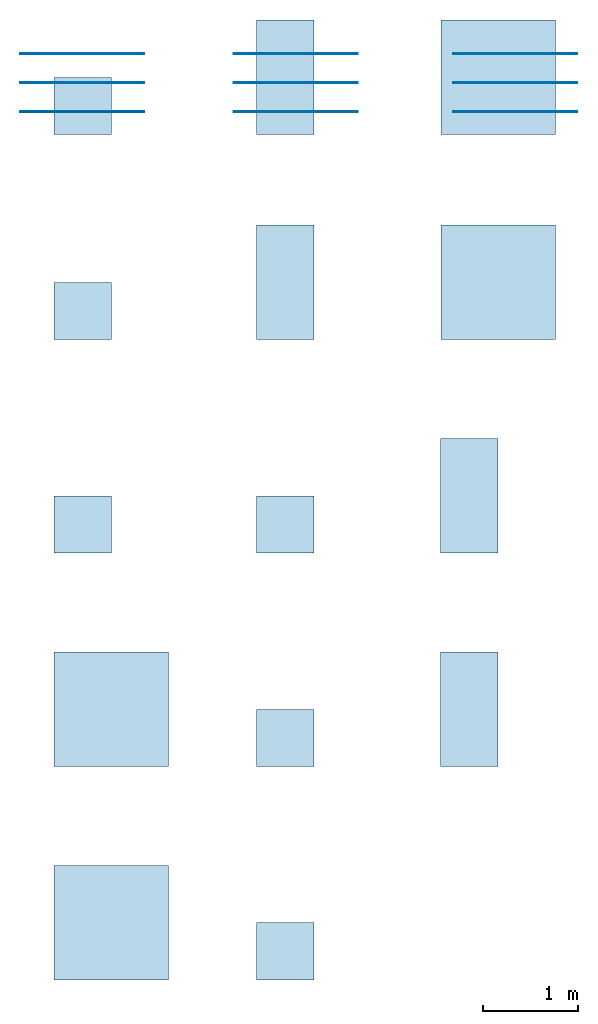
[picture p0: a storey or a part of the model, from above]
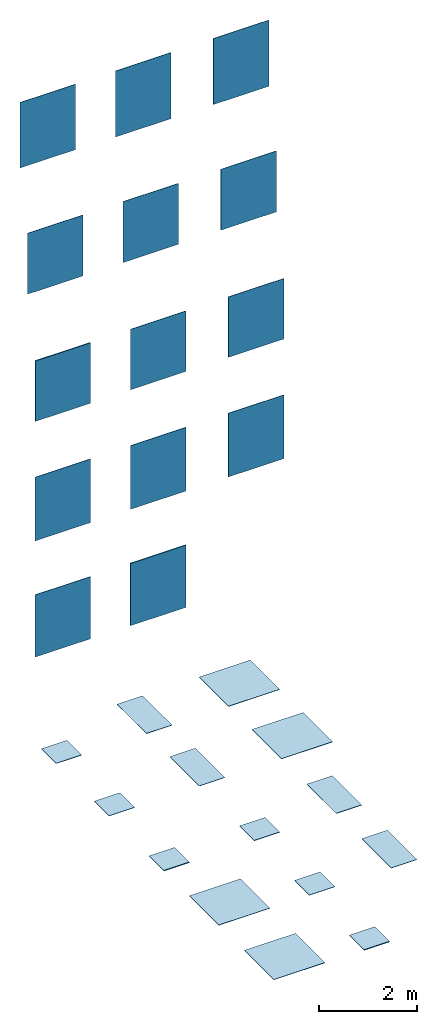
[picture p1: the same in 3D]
Properties of the parts of a building model (IFC2X3), part 2 of 4

# IfcSlab: Floor:Floor_Tiles_Refin-Orobica-Bianca-60x120 OQ59, Floor:Floor_Tiles_Refin-Orobica-Bianca-60x120 OQ59:339650
Type - COBie - AccessibilityPerformance: N/A; AssetIdentifier: N/A; AssetType: FIXED; BarCode: N/A; Category: Pr_35_93_96_19:Ceramic tiles; CodePerformance: BS 5385; Color: WHITE; Constituents: N/A; Description: PORCELAIN STONEWARE TILE; DurationUnit: YEAR; ExpectedLife: N/A; Features: N/A; Grade: N/A; InstallationDate: 31/12/1900 23:59:59; Manufacturer: info@refin.it; Material: PORCELAIN STONEWARE; ModelNumber: OQ59; ModelReference: OQ59; Name: Orobica_Bianca_60X120 R; NominalHeight: 9 mm; NominalLength: 600 mm; NominalWidth: 1200 mm; ReplacementCost: N/A; SerialNumber: N/A; Shape: RECTANGULAR; Size: 60X120; SustainabilityPerformance: N/A; TagNumber: N/A; WarrantyDescription: N/A; WarrantyDurationLabor: N/A; WarrantyDurationParts: N/A; WarrantyDurationUnit: YEAR; WarrantyGuarantorLabor: N/A; WarrantyGuarantorParts: N/A; WarrantyStartDate: 31/12/1900 23:59:59
Type - DoPAndProductCertification - HarmonizedTechnicalSpecification: EN 14411:2015; DeclarationPerformanceNumber: CPR_01; UniqueIdentificationCodeOfTheProductType: Dry-pressed ceramic tiles,with water absorption Eb<0,5%; SystemOfAssessmentAndVerificationOfCostancyOfPperformance (AVCP): SYSTEM 4; NameAndIdentificationNumberOfNotifiedLaboratory: N/A; CertificateNumber: N/A; ReactionToFire: A1FL/A1; ReleaseOfDangerousSubstanceCadmium: NPD mg/dm2; ReleaseOfDangerousSubstanceLead: NPD mg/dm2; BreakingStrength: > 1300 N; BondStrengthAdhesion: NPD N/mm2; ThermalShockResistance: PASS; Tactility: NPD; DurabilityForInternalUse: PASS; DurabilityExternalUseFreezeThawResistance: PASS; VoluntaryOrNotSubjectToCEMarking: Y/N; IntendedUse: INTERNAL/EXTERNAL; TensileStrengthOrModulusOfRupture: > 35 N/mm2; SlipperinessDIN51130_RampWithOil: R10; SlipperinessDIN51097_RampBarefoot: N/A; SlipperinessDIN51131_Tribometer: N/A; SlipperinessENV12633_PendulumTester: RD = N/A; SlipperinessXPCENTS16165_RampTest: N/A; SlipperinessBCRA_Tribometer: Asciutto > 0,40 / Bagnato > 0,40; SlipperinessBOT3000_Tribometer: > 0,42 Wet; UPECMarkCertification: N/A; UNIMarkCertification: N/A
Type - OtherThecnicalFeatures - DimensionsLengthAndWidth: 0.3; DimensionsThickness: 5; DimensionsStraightness: 0.3; DimensionsRectangularity: 0.3; DimensionsSurfaceFlatness: 0.4; SurfaceQuality: 5; WaterAbsorption: Ev<0.5%; ApparentDensity: N/A g/cm3; ModulusOfRupture: > 35 N/mm2; ImpactResistance: > 0.55; DeepAbrasionResistance: < 175 mm3; SurfaceAbrasionResistance: N/A (classe); LinearThermalExpansion: < 7 10-6/°C; MoistureExpansion: < 0.01; CrazingResistance: N/A; FrostResistance: RESISTENTE; ChemicalResistance: A,LA,HA (classe); StainsResistance: 5 (classe); ThermalConductivity: 1.3 W/m.K; ElectricalConductivity: N/A MW; CompressionResistance: 250 Mpa; HardnessMohsScale: N/A (classe); Light ReflectanceValueLRV: 56 %; LightAndColourFastness: N/A; AntibacterialProperties: N/A (numero puro)
Type - Ambiental Sustainability - EPDType: PRODUCT-SPECIFIC TYPE III EPD; EPDDocument: https://www.refin.it/download/certifications/REFIN_EPD_it.pdf; EnvironmentalProductDeclarationEPD: Y; ISO9001Certification: https://www.refin.it/download/certifications/iso9001.pdf; Ecolabel UE: Y/N; EcolabelCertification: https://www.refin.it/download/certifications/PEF_CeramicheRefin_IT.pdf; EMASCertification/Document: N/A; HealthProductDeclarationHPDCertification/self declaration: N/A; FicheDeDéclarationEnvironnementaleEtSanitaireFDESCertification: https://www.refin.it/download/certifications/refin_fdes.pdf; RecycledContentPreconsumerCertification: https://www.refin.it/download/certifications/leed.pdf; SolarReflectance_InitialValue: 72; SolarReflectance_After3YearValue: N/A; SolarReflectanceCertification: N/A; SolarReflectanceIndexSRICertification: N/A; ZeroVOCMineralBasedProduct: Y; VOCIndoorAirQualityCertification: N/A; RawMaterialSourceAndExtractionDocument: N/A; RecyclableProductPackaging: Y; REACHCompliant: Y; AsbestosFreeMaterial: Y; FormaldehydeFreeMaterial: Y; CAMCompliantDeclaration: N/A; ISO45001Certification: N/A; ISO50001Certification: N/A
Type - Pset_EnvironmentalImpactIndicator - Reference: N/A; FunctionalUnitReference: N/A; Unit: m2; LifeCyclePhase: A1,A2,A3,A4,A5,B1,B2,B3,B4,B5,B6,B7,C1,C2,C3,C4,D; ExpectedServiceLife: 60 YEARS; TotalPrimaryEnergyConsumptionPerUnit: 234; WaterConsumptionPerUnit: 0.0522; HazardousWastePerUnit: 0.00301; NonHazardousWastePerUnit: 10.4; ClimateChangePerUnit: 12.8; AtmosphericAcidificationPerUnit: 0.0485; RenewableEnergyConsumptionPerUnit: 44.5; NonRenewableEnergyConsumptionPerUnit: 189; ResourceDepletionPerUnit: 0.0000365; InertWastePerUnit: N/A; RadioactiveWastePerUnit: 0.00254; StratosphericOzoneLayerDestructionPerUnit: 0.0000000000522; PhotochemicalOzoneFormationPerUnit: 0.00302; EutrophicationPerUnit: 0.00445
Type - Pset_EnvironmentalImpactValues - TotalPrimaryEnergyConsumption: N/A; WaterConsumption: N/A; HazardousWaste: N/A; NonHazardousWaste: N/A; ClimateChange: N/A; AtmosphericAcidification: N/A; RenewableEnergyConsumption: N/A; NonRenewableEnergyConsumption: N/A; ResourceDepletion: N/A; InertWaste: N/A; RadioactiveWaste: N/A; StratosphericOzoneLayerDestruction: N/A; PhotochemicalOzoneFormation: N/A; Eutrophication: N/A; LeadInTime: N/A; Duration: N/A; LeadOutTime: N/A
Pset_ProductRequirements - Category: Floors; sets with these values: 2
Pset_QuantityTakeOff - sets with these values: 2
Pset_SlabCommon - LoadBearing: no; PitchAngle: 0 deg

# IfcSlab: Floor:Floor_Tiles_Refin-Orobica-Bianca-60x60 OQ63, Floor:Floor_Tiles_Refin-Orobica-Bianca-60x60 OQ63:349446
In: Level 0
Type - PredefinedType: FLOOR; Material: Orobica-Bianca-60x60 OQ63 9 mm, <Unnamed> 1 mm
Type - Pset_ConcreteElementGeneral - FireRating: INERT
Type - Pset_ElementShading - Roughness: 914.4 mm; Color: WHITE
Type - Pset_FireRatingProperties - SurfaceSpreadOfFlame: INERT
Type - Pset_ManufacturerOccurrence - BarCode: N/A; SerialNumber: N/A
Type - Pset_ManufacturerTypeInformation - ArticleNumber: OQ63; ModelReference: OQ63; ModelLabel: BIANCA R 60X60; Manufacturer: info@refin.it; ProductionYear: N/A; GlobalTradeItemNumber: N/A; AssemblyPlace: N/A
Type - Pset_PrecastConcreteElementGeneral - SerialNumber: N/A
Type - Pset_ProductRequirements - Name: Orobica_Bianca_60X60 R; Category: Pr_35_93_96_19:Ceramic tiles
Type - Pset_QuantityTakeOff - Reference: N/A
Type - Pset_ReinforcementBarPitchOfSlab - Description: PORCELAIN STONEWARE TILE; Reference: N/A
Type - Pset_SlabCommon - Reference: N/A; IsExternal: no; AcousticRating: N/A; FireRating: INERT; SurfaceSpreadOfFlame: INERT
Type - Pset_Warranty - WarrantyContent: N/A; Exclusions: N/A; WarrantyEndDate: N/A; IsExtendedWarranty: N/A; WarrantyPeriod: N/A; PointOfContact: N/A
Type - Pset_CoveringCommon - Reference: N/A; Status: N/A; AcousticRating: N/A; FlammabilityRating: INERT; FragilityRating: INERT; Combustible: FALSE; SurfaceSpreadOfFlame: INERT; Finish: MATT; IsExternal: N/A; ThermalTransmittance: N/A; FireRating: INERT
Type - Pset_CoveringFlooring - HasNonSkidSurface: TRUE; HasAntiStaticSurface: FALSE
Type - Pset_Condition - AssessmentDate: N/A; AssessmentCondition: N/A; AssessmentDescription: N/A
Type - Pset_ServiceLife - ServiceLifeDuration: N/A; MeanTimeBetweenFailure: N/A
Type - COBie - AccessibilityPerformance: N/A; AssetIdentifier: N/A; AssetType: FIXED; BarCode: N/A; Category: Pr_35_93_96_19:Ceramic tiles; CodePerformance: BS 5385; Color: WHITE; Constituents: N/A; Description: PORCELAIN STONEWARE TILE; DurationUnit: YEAR; ExpectedLife: N/A; Features: N/A; Grade: N/A; InstallationDate: 31/12/1900 23:59:59; Manufacturer: info@refin.it; Material: PORCELAIN STONEWARE; ModelNumber: OQ63; ModelReference: OQ63; Name: Orobica_Bianca_60X60 R; NominalHeight: 9 mm; NominalLength: 600 mm; NominalWidth: 600 mm; ReplacementCost: N/A; SerialNumber: N/A; Shape: SQUARE; Size: 60X60; SustainabilityPerformance: N/A; TagNumber: N/A; WarrantyDescription: N/A; WarrantyDurationLabor: N/A; WarrantyDurationParts: N/A; WarrantyDurationUnit: YEAR; WarrantyGuarantorLabor: N/A; WarrantyGuarantorParts: N/A; WarrantyStartDate: 31/12/1900 23:59:59
Type - DoPAndProductCertification - HarmonizedTechnicalSpecification: EN 14411:2015; DeclarationPerformanceNumber: CPR_01; UniqueIdentificationCodeOfTheProductType: Dry-pressed ceramic tiles,with water absorption Eb<0,5%; SystemOfAssessmentAndVerificationOfCostancyOfPperformance (AVCP): SYSTEM 4; NameAndIdentificationNumberOfNotifiedLaboratory: N/A; CertificateNumber: N/A; ReactionToFire: A1FL/A1; ReleaseOfDangerousSubstanceCadmium: NPD mg/dm2; ReleaseOfDangerousSubstanceLead: NPD mg/dm2; BreakingStrength: > 1300 N; BondStrengthAdhesion: NPD N/mm2; ThermalShockResistance: PASS; Tactility: NPD; DurabilityForInternalUse: PASS; DurabilityExternalUseFreezeThawResistance: PASS; VoluntaryOrNotSubjectToCEMarking: Y/N; IntendedUse: INTERNAL/EXTERNAL; TensileStrengthOrModulusOfRupture: > 35 N/mm2; SlipperinessDIN51130_RampWithOil: R10; SlipperinessDIN51097_RampBarefoot: N/A; SlipperinessDIN51131_Tribometer: N/A; SlipperinessENV12633_PendulumTester: RD = N/A; SlipperinessXPCENTS16165_RampTest: N/A; SlipperinessBCRA_Tribometer: Asciutto > 0,40 / Bagnato > 0,40; SlipperinessBOT3000_Tribometer: > 0,42 Wet; UPECMarkCertification: N/A; UNIMarkCertification: N/A
Type - OtherThecnicalFeatures - DimensionsLengthAndWidth: 0.3; DimensionsThickness: 5; DimensionsStraightness: 0.3; DimensionsRectangularity: 0.3; DimensionsSurfaceFlatness: 0.4; SurfaceQuality: 5; WaterAbsorption: Ev<0.5%; ApparentDensity: N/A g/cm3; ModulusOfRupture: > 35 N/mm2; ImpactResistance: > 0.55; DeepAbrasionResistance: < 175 mm3; SurfaceAbrasionResistance: N/A (classe); LinearThermalExpansion: < 7 10-6/°C; MoistureExpansion: < 0.01; CrazingResistance: N/A; FrostResistance: RESISTENTE; ChemicalResistance: A,LA,HA (classe); StainsResistance: 5 (classe); ThermalConductivity: 1.3 W/m.K; ElectricalConductivity: N/A MW; CompressionResistance: 250 Mpa; HardnessMohsScale: N/A (classe); Light ReflectanceValueLRV: 56 %; LightAndColourFastness: N/A; AntibacterialProperties: N/A (numero puro)
Type - Ambiental Sustainability - EPDType: PRODUCT-SPECIFIC TYPE III EPD; EPDDocument: https://www.refin.it/download/certifications/REFIN_EPD_it.pdf; EnvironmentalProductDeclarationEPD: Y; ISO9001Certification: https://www.refin.it/download/certifications/iso9001.pdf; Ecolabel UE: Y/N; EcolabelCertification: https://www.refin.it/download/certifications/PEF_CeramicheRefin_IT.pdf; EMASCertification/Document: N/A; HealthProductDeclarationHPDCertification/self declaration: N/A; FicheDeDéclarationEnvironnementaleEtSanitaireFDESCertification: https://www.refin.it/download/certifications/refin_fdes.pdf; RecycledContentPreconsumerCertification: https://www.refin.it/download/certifications/leed.pdf; SolarReflectance_InitialValue: 72; SolarReflectance_After3YearValue: N/A; SolarReflectanceCertification: N/A; SolarReflectanceIndexSRICertification: N/A; ZeroVOCMineralBasedProduct: Y; VOCIndoorAirQualityCertification: N/A; RawMaterialSourceAndExtractionDocument: N/A; RecyclableProductPackaging: Y; REACHCompliant: Y; AsbestosFreeMaterial: Y; FormaldehydeFreeMaterial: Y; CAMCompliantDeclaration: N/A; ISO45001Certification: N/A; ISO50001Certification: N/A
Type - Pset_EnvironmentalImpactIndicator - Reference: N/A; FunctionalUnitReference: N/A; Unit: m2; LifeCyclePhase: A1,A2,A3,A4,A5,B1,B2,B3,B4,B5,B6,B7,C1,C2,C3,C4,D; ExpectedServiceLife: 60 YEARS; TotalPrimaryEnergyConsumptionPerUnit: 234; WaterConsumptionPerUnit: 0.0522; HazardousWastePerUnit: 0.00301; NonHazardousWastePerUnit: 10.4; ClimateChangePerUnit: 12.8; AtmosphericAcidificationPerUnit: 0.0485; RenewableEnergyConsumptionPerUnit: 44.5; NonRenewableEnergyConsumptionPerUnit: 189; ResourceDepletionPerUnit: 0.0000365; InertWastePerUnit: N/A; RadioactiveWastePerUnit: 0.00254; StratosphericOzoneLayerDestructionPerUnit: 0.0000000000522; PhotochemicalOzoneFormationPerUnit: 0.00302; EutrophicationPerUnit: 0.00445
Type - Pset_EnvironmentalImpactValues - TotalPrimaryEnergyConsumption: N/A; WaterConsumption: N/A; HazardousWaste: N/A; NonHazardousWaste: N/A; ClimateChange: N/A; AtmosphericAcidification: N/A; RenewableEnergyConsumption: N/A; NonRenewableEnergyConsumption: N/A; ResourceDepletion: N/A; InertWaste: N/A; RadioactiveWaste: N/A; StratosphericOzoneLayerDestruction: N/A; PhotochemicalOzoneFormation: N/A; Eutrophication: N/A; LeadInTime: N/A; Duration: N/A; LeadOutTime: N/A
Pset_ProductRequirements - Category: Floors; sets with these values: 2
Pset_QuantityTakeOff - sets with these values: 2
Pset_SlabCommon - LoadBearing: no; PitchAngle: 0 deg

# IfcSlab: Floor:Floor_Tiles_Refin-Orobica-Grigia-120x120 OQ56, Floor:Floor_Tiles_Refin-Orobica-Grigia-120x120 OQ56:350395
In: Level 0
Type - PredefinedType: FLOOR; Material: Orobica-Grigia-120x120 OQ56 9 mm, <Unnamed> 1 mm
Type - Pset_ConcreteElementGeneral - FireRating: INERT
Type - Pset_ElementShading - Roughness: 914.4 mm; Color: GREY
Type - Pset_FireRatingProperties - SurfaceSpreadOfFlame: INERT
Type - Pset_ManufacturerOccurrence - BarCode: N/A; SerialNumber: N/A
Type - Pset_ManufacturerTypeInformation - ArticleNumber: OQ56; ModelReference: OQ56; ModelLabel: GRIGIA R 120X120; Manufacturer: info@refin.it; ProductionYear: N/A; GlobalTradeItemNumber: N/A; AssemblyPlace: N/A
Type - Pset_PrecastConcreteElementGeneral - SerialNumber: N/A
Type - Pset_ProductRequirements - Name: Orobica_Grigia_120X120 R; Category: Pr_35_93_96_19:Ceramic tiles
Type - Pset_QuantityTakeOff - Reference: N/A
Type - Pset_ReinforcementBarPitchOfSlab - Description: PORCELAIN STONEWARE TILE; Reference: N/A
Type - Pset_SlabCommon - Reference: N/A; IsExternal: no; AcousticRating: N/A; FireRating: INERT; SurfaceSpreadOfFlame: INERT
Type - Pset_Warranty - WarrantyContent: N/A; Exclusions: N/A; WarrantyEndDate: N/A; IsExtendedWarranty: N/A; WarrantyPeriod: N/A; PointOfContact: N/A
Type - Pset_CoveringCommon - Reference: N/A; Status: N/A; AcousticRating: N/A; FlammabilityRating: INERT; FragilityRating: INERT; Combustible: FALSE; SurfaceSpreadOfFlame: INERT; Finish: MATT; IsExternal: N/A; ThermalTransmittance: N/A; FireRating: INERT
Type - Pset_CoveringFlooring - HasNonSkidSurface: TRUE; HasAntiStaticSurface: FALSE
Type - Pset_Condition - AssessmentDate: N/A; AssessmentCondition: N/A; AssessmentDescription: N/A
Type - Pset_ServiceLife - ServiceLifeDuration: N/A; MeanTimeBetweenFailure: N/A
Type - COBie - AccessibilityPerformance: N/A; AssetIdentifier: N/A; AssetType: FIXED; BarCode: N/A; Category: Pr_35_93_96_19:Ceramic tiles; CodePerformance: BS 5385; Color: GREY; Constituents: N/A; Description: PORCELAIN STONEWARE TILE; DurationUnit: YEAR; ExpectedLife: N/A; Features: N/A; Grade: N/A; InstallationDate: 31/12/1900 23:59:59; Manufacturer: info@refin.it; Material: PORCELAIN STONEWARE; ModelNumber: OQ56; ModelReference: OQ56; Name: Orobica_Grigia_120X120 R; NominalHeight: 9 mm; NominalLength: 1200 mm; NominalWidth: 1200 mm; ReplacementCost: N/A; SerialNumber: N/A; Shape: SQUARE; Size: 120X120; SustainabilityPerformance: N/A; TagNumber: N/A; WarrantyDescription: N/A; WarrantyDurationLabor: N/A; WarrantyDurationParts: N/A; WarrantyDurationUnit: YEAR; WarrantyGuarantorLabor: N/A; WarrantyGuarantorParts: N/A; WarrantyStartDate: 31/12/1900 23:59:59
Type - DoPAndProductCertification - HarmonizedTechnicalSpecification: EN 14411:2015; DeclarationPerformanceNumber: CPR_01; UniqueIdentificationCodeOfTheProductType: Dry-pressed ceramic tiles,with water absorption Eb<0,5%; SystemOfAssessmentAndVerificationOfCostancyOfPperformance (AVCP): SYSTEM 4; NameAndIdentificationNumberOfNotifiedLaboratory: N/A; CertificateNumber: N/A; ReactionToFire: A1FL/A1; ReleaseOfDangerousSubstanceCadmium: NPD mg/dm2; ReleaseOfDangerousSubstanceLead: NPD mg/dm2; BreakingStrength: > 1300 N; BondStrengthAdhesion: NPD N/mm2; ThermalShockResistance: PASS; Tactility: NPD; DurabilityForInternalUse: PASS; DurabilityExternalUseFreezeThawResistance: PASS; VoluntaryOrNotSubjectToCEMarking: Y/N; IntendedUse: INTERNAL/EXTERNAL; TensileStrengthOrModulusOfRupture: > 35 N/mm2; SlipperinessDIN51130_RampWithOil: R10; SlipperinessDIN51097_RampBarefoot: N/A; SlipperinessDIN51131_Tribometer: N/A; SlipperinessENV12633_PendulumTester: RD = N/A; SlipperinessXPCENTS16165_RampTest: N/A; SlipperinessBCRA_Tribometer: Asciutto > 0,40 / Bagnato > 0,40; SlipperinessBOT3000_Tribometer: > 0,42 Wet; UPECMarkCertification: N/A; UNIMarkCertification: N/A
Type - OtherThecnicalFeatures - DimensionsLengthAndWidth: 0.3; DimensionsThickness: 5; DimensionsStraightness: 0.3; DimensionsRectangularity: 0.3; DimensionsSurfaceFlatness: 0.4; SurfaceQuality: 5; WaterAbsorption: Ev<0.5%; ApparentDensity: N/A g/cm3; ModulusOfRupture: > 35 N/mm2; ImpactResistance: > 0.55; DeepAbrasionResistance: < 175 mm3; SurfaceAbrasionResistance: N/A (classe); LinearThermalExpansion: < 7 10-6/°C; MoistureExpansion: < 0.01; CrazingResistance: N/A; FrostResistance: RESISTENTE; ChemicalResistance: A,LA,HA (classe); StainsResistance: 5 (classe); ThermalConductivity: 1.3 W/m.K; ElectricalConductivity: N/A MW; CompressionResistance: 250 Mpa; HardnessMohsScale: N/A (classe); Light ReflectanceValueLRV: 27 %; LightAndColourFastness: N/A; AntibacterialProperties: N/A (numero puro)
Type - Ambiental Sustainability - EPDType: PRODUCT-SPECIFIC TYPE III EPD; EPDDocument: https://www.refin.it/download/certifications/REFIN_EPD_it.pdf; EnvironmentalProductDeclarationEPD: Y; ISO9001Certification: https://www.refin.it/download/certifications/iso9001.pdf; Ecolabel UE: Y/N; EcolabelCertification: https://www.refin.it/download/certifications/PEF_CeramicheRefin_IT.pdf; EMASCertification/Document: N/A; HealthProductDeclarationHPDCertification/self declaration: N/A; FicheDeDéclarationEnvironnementaleEtSanitaireFDESCertification: https://www.refin.it/download/certifications/refin_fdes.pdf; RecycledContentPreconsumerCertification: https://www.refin.it/download/certifications/leed.pdf; SolarReflectance_InitialValue: 38; SolarReflectance_After3YearValue: N/A; SolarReflectanceCertification: N/A; SolarReflectanceIndexSRICertification: N/A; ZeroVOCMineralBasedProduct: Y; VOCIndoorAirQualityCertification: N/A; RawMaterialSourceAndExtractionDocument: N/A; RecyclableProductPackaging: Y; REACHCompliant: Y; AsbestosFreeMaterial: Y; FormaldehydeFreeMaterial: Y; CAMCompliantDeclaration: N/A; ISO45001Certification: N/A; ISO50001Certification: N/A
Type - Pset_EnvironmentalImpactIndicator - Reference: N/A; FunctionalUnitReference: N/A; Unit: m2; LifeCyclePhase: A1,A2,A3,A4,A5,B1,B2,B3,B4,B5,B6,B7,C1,C2,C3,C4,D; ExpectedServiceLife: 60 YEARS; TotalPrimaryEnergyConsumptionPerUnit: 234; WaterConsumptionPerUnit: 0.0522; HazardousWastePerUnit: 0.00301; NonHazardousWastePerUnit: 10.4; ClimateChangePerUnit: 12.8; AtmosphericAcidificationPerUnit: 0.0485; RenewableEnergyConsumptionPerUnit: 44.5; NonRenewableEnergyConsumptionPerUnit: 189; ResourceDepletionPerUnit: 0.0000365; InertWastePerUnit: N/A; RadioactiveWastePerUnit: 0.00254; StratosphericOzoneLayerDestructionPerUnit: 0.0000000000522; PhotochemicalOzoneFormationPerUnit: 0.00302; EutrophicationPerUnit: 0.00445
Type - Pset_EnvironmentalImpactValues - TotalPrimaryEnergyConsumption: N/A; WaterConsumption: N/A; HazardousWaste: N/A; NonHazardousWaste: N/A; ClimateChange: N/A; AtmosphericAcidification: N/A; RenewableEnergyConsumption: N/A; NonRenewableEnergyConsumption: N/A; ResourceDepletion: N/A; InertWaste: N/A; RadioactiveWaste: N/A; StratosphericOzoneLayerDestruction: N/A; PhotochemicalOzoneFormation: N/A; Eutrophication: N/A; LeadInTime: N/A; Duration: N/A; LeadOutTime: N/A
Pset_ProductRequirements - Category: Floors; sets with these values: 2
Pset_QuantityTakeOff - sets with these values: 2
Pset_SlabCommon - LoadBearing: no; PitchAngle: 0 deg

# IfcSlab: Floor:Floor_Tiles_Refin-Orobica-Grigia-60x120 OQ60, Floor:Floor_Tiles_Refin-Orobica-Grigia-60x120 OQ60:349744
In: Level 0
Type - PredefinedType: FLOOR; Material: Orobica-Grigia-60x120 OQ60 9 mm, <Unnamed> 1 mm
Type - Pset_ConcreteElementGeneral - FireRating: INERT
Type - Pset_ElementShading - Roughness: 914.4 mm; Color: GREY
Type - Pset_FireRatingProperties - SurfaceSpreadOfFlame: INERT
Type - Pset_ManufacturerOccurrence - BarCode: N/A; SerialNumber: N/A
Type - Pset_ManufacturerTypeInformation - ArticleNumber: OQ60; ModelReference: OQ60; ModelLabel: GRIGIA R 60X120; Manufacturer: info@refin.it; ProductionYear: N/A; GlobalTradeItemNumber: N/A; AssemblyPlace: N/A
Type - Pset_PrecastConcreteElementGeneral - SerialNumber: N/A
Type - Pset_ProductRequirements - Name: Orobica_Grigia_60X120 R; Category: Pr_35_93_96_19:Ceramic tiles
Type - Pset_QuantityTakeOff - Reference: N/A
Type - Pset_ReinforcementBarPitchOfSlab - Description: PORCELAIN STONEWARE TILE; Reference: N/A
Type - Pset_SlabCommon - Reference: N/A; IsExternal: no; AcousticRating: N/A; FireRating: INERT; SurfaceSpreadOfFlame: INERT
Type - Pset_Warranty - WarrantyContent: N/A; Exclusions: N/A; WarrantyEndDate: N/A; IsExtendedWarranty: N/A; WarrantyPeriod: N/A; PointOfContact: N/A
Type - Pset_CoveringCommon - Reference: N/A; Status: N/A; AcousticRating: N/A; FlammabilityRating: INERT; FragilityRating: INERT; Combustible: FALSE; SurfaceSpreadOfFlame: INERT; Finish: MATT; IsExternal: N/A; ThermalTransmittance: N/A; FireRating: INERT
Type - Pset_CoveringFlooring - HasNonSkidSurface: TRUE; HasAntiStaticSurface: FALSE
Type - Pset_Condition - AssessmentDate: N/A; AssessmentCondition: N/A; AssessmentDescription: N/A
Type - Pset_ServiceLife - ServiceLifeDuration: N/A; MeanTimeBetweenFailure: N/A
Type - COBie - AccessibilityPerformance: N/A; AssetIdentifier: N/A; AssetType: FIXED; BarCode: N/A; Category: Pr_35_93_96_19:Ceramic tiles; CodePerformance: BS 5385; Color: GREY; Constituents: N/A; Description: PORCELAIN STONEWARE TILE; DurationUnit: YEAR; ExpectedLife: N/A; Features: N/A; Grade: N/A; InstallationDate: 31/12/1900 23:59:59; Manufacturer: info@refin.it; Material: PORCELAIN STONEWARE; ModelNumber: OQ60; ModelReference: OQ60; Name: Orobica_Grigia_60X120 R; NominalHeight: 9 mm; NominalLength: 600 mm; NominalWidth: 1200 mm; ReplacementCost: N/A; SerialNumber: N/A; Shape: RECTANGULAR; Size: 60X120; SustainabilityPerformance: N/A; TagNumber: N/A; WarrantyDescription: N/A; WarrantyDurationLabor: N/A; WarrantyDurationParts: N/A; WarrantyDurationUnit: YEAR; WarrantyGuarantorLabor: N/A; WarrantyGuarantorParts: N/A; WarrantyStartDate: 31/12/1900 23:59:59
Type - DoPAndProductCertification - HarmonizedTechnicalSpecification: EN 14411:2015; DeclarationPerformanceNumber: CPR_01; UniqueIdentificationCodeOfTheProductType: Dry-pressed ceramic tiles,with water absorption Eb<0,5%; SystemOfAssessmentAndVerificationOfCostancyOfPperformance (AVCP): SYSTEM 4; NameAndIdentificationNumberOfNotifiedLaboratory: N/A; CertificateNumber: N/A; ReactionToFire: A1FL/A1; ReleaseOfDangerousSubstanceCadmium: NPD mg/dm2; ReleaseOfDangerousSubstanceLead: NPD mg/dm2; BreakingStrength: > 1300 N; BondStrengthAdhesion: NPD N/mm2; ThermalShockResistance: PASS; Tactility: NPD; DurabilityForInternalUse: PASS; DurabilityExternalUseFreezeThawResistance: PASS; VoluntaryOrNotSubjectToCEMarking: Y/N; IntendedUse: INTERNAL/EXTERNAL; TensileStrengthOrModulusOfRupture: > 35 N/mm2; SlipperinessDIN51130_RampWithOil: R10; SlipperinessDIN51097_RampBarefoot: N/A; SlipperinessDIN51131_Tribometer: N/A; SlipperinessENV12633_PendulumTester: RD = N/A; SlipperinessXPCENTS16165_RampTest: N/A; SlipperinessBCRA_Tribometer: Asciutto > 0,40 / Bagnato > 0,40; SlipperinessBOT3000_Tribometer: > 0,42 Wet; UPECMarkCertification: N/A; UNIMarkCertification: N/A
Type - OtherThecnicalFeatures - DimensionsLengthAndWidth: 0.3; DimensionsThickness: 5; DimensionsStraightness: 0.3; DimensionsRectangularity: 0.3; DimensionsSurfaceFlatness: 0.4; SurfaceQuality: 5; WaterAbsorption: Ev<0.5%; ApparentDensity: N/A g/cm3; ModulusOfRupture: > 35 N/mm2; ImpactResistance: > 0.55; DeepAbrasionResistance: < 175 mm3; SurfaceAbrasionResistance: N/A (classe); LinearThermalExpansion: < 7 10-6/°C; MoistureExpansion: < 0.01; CrazingResistance: N/A; FrostResistance: RESISTENTE; ChemicalResistance: A,LA,HA (classe); StainsResistance: 5 (classe); ThermalConductivity: 1.3 W/m.K; ElectricalConductivity: N/A MW; CompressionResistance: 250 Mpa; HardnessMohsScale: N/A (classe); Light ReflectanceValueLRV: 27 %; LightAndColourFastness: N/A; AntibacterialProperties: N/A (numero puro)
Type - Ambiental Sustainability - EPDType: PRODUCT-SPECIFIC TYPE III EPD; EPDDocument: https://www.refin.it/download/certifications/REFIN_EPD_it.pdf; EnvironmentalProductDeclarationEPD: Y; ISO9001Certification: https://www.refin.it/download/certifications/iso9001.pdf; Ecolabel UE: Y/N; EcolabelCertification: https://www.refin.it/download/certifications/PEF_CeramicheRefin_IT.pdf; EMASCertification/Document: N/A; HealthProductDeclarationHPDCertification/self declaration: N/A; FicheDeDéclarationEnvironnementaleEtSanitaireFDESCertification: https://www.refin.it/download/certifications/refin_fdes.pdf; RecycledContentPreconsumerCertification: https://www.refin.it/download/certifications/leed.pdf; SolarReflectance_InitialValue: 38; SolarReflectance_After3YearValue: N/A; SolarReflectanceCertification: N/A; SolarReflectanceIndexSRICertification: N/A; ZeroVOCMineralBasedProduct: Y; VOCIndoorAirQualityCertification: N/A; RawMaterialSourceAndExtractionDocument: N/A; RecyclableProductPackaging: Y; REACHCompliant: Y; AsbestosFreeMaterial: Y; FormaldehydeFreeMaterial: Y; CAMCompliantDeclaration: N/A; ISO45001Certification: N/A; ISO50001Certification: N/A
Type - Pset_EnvironmentalImpactIndicator - Reference: N/A; FunctionalUnitReference: N/A; Unit: m2; LifeCyclePhase: A1,A2,A3,A4,A5,B1,B2,B3,B4,B5,B6,B7,C1,C2,C3,C4,D; ExpectedServiceLife: 60 YEARS; TotalPrimaryEnergyConsumptionPerUnit: 234; WaterConsumptionPerUnit: 0.0522; HazardousWastePerUnit: 0.00301; NonHazardousWastePerUnit: 10.4; ClimateChangePerUnit: 12.8; AtmosphericAcidificationPerUnit: 0.0485; RenewableEnergyConsumptionPerUnit: 44.5; NonRenewableEnergyConsumptionPerUnit: 189; ResourceDepletionPerUnit: 0.0000365; InertWastePerUnit: N/A; RadioactiveWastePerUnit: 0.00254; StratosphericOzoneLayerDestructionPerUnit: 0.0000000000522; PhotochemicalOzoneFormationPerUnit: 0.00302; EutrophicationPerUnit: 0.00445
Type - Pset_EnvironmentalImpactValues - TotalPrimaryEnergyConsumption: N/A; WaterConsumption: N/A; HazardousWaste: N/A; NonHazardousWaste: N/A; ClimateChange: N/A; AtmosphericAcidification: N/A; RenewableEnergyConsumption: N/A; NonRenewableEnergyConsumption: N/A; ResourceDepletion: N/A; InertWaste: N/A; RadioactiveWaste: N/A; StratosphericOzoneLayerDestruction: N/A; PhotochemicalOzoneFormation: N/A; Eutrophication: N/A; LeadInTime: N/A; Duration: N/A; LeadOutTime: N/A
Pset_ProductRequirements - Category: Floors; sets with these values: 2
Pset_QuantityTakeOff - sets with these values: 2
Pset_SlabCommon - LoadBearing: no; PitchAngle: 0 deg

# IfcSlab: Floor:Floor_Tiles_Refin-Orobica-Grigia-60x60 OQ64, Floor:Floor_Tiles_Refin-Orobica-Grigia-60x60 OQ64:349760
In: Level 0
Type - PredefinedType: FLOOR; Material: Orobica-Grigia-60x60 OQ64 9 mm, <Unnamed> 1 mm
Type - Pset_ConcreteElementGeneral - FireRating: INERT
Type - Pset_ElementShading - Roughness: 914.4 mm; Color: GREY
Type - Pset_FireRatingProperties - SurfaceSpreadOfFlame: INERT
Type - Pset_ManufacturerOccurrence - BarCode: N/A; SerialNumber: N/A
Type - Pset_ManufacturerTypeInformation - ArticleNumber: OQ64; ModelReference: OQ64; ModelLabel: GRIGIA R 60X60; Manufacturer: info@refin.it; ProductionYear: N/A; GlobalTradeItemNumber: N/A; AssemblyPlace: N/A
Type - Pset_PrecastConcreteElementGeneral - SerialNumber: N/A
Type - Pset_ProductRequirements - Name: Orobica_Grigia_60X60 R; Category: Pr_35_93_96_19:Ceramic tiles
Type - Pset_QuantityTakeOff - Reference: N/A
Type - Pset_ReinforcementBarPitchOfSlab - Description: PORCELAIN STONEWARE TILE; Reference: N/A
Type - Pset_SlabCommon - Reference: N/A; IsExternal: no; AcousticRating: N/A; FireRating: INERT; SurfaceSpreadOfFlame: INERT
Type - Pset_Warranty - WarrantyContent: N/A; Exclusions: N/A; WarrantyEndDate: N/A; IsExtendedWarranty: N/A; WarrantyPeriod: N/A; PointOfContact: N/A
Type - Pset_CoveringCommon - Reference: N/A; Status: N/A; AcousticRating: N/A; FlammabilityRating: INERT; FragilityRating: INERT; Combustible: FALSE; SurfaceSpreadOfFlame: INERT; Finish: MATT; IsExternal: N/A; ThermalTransmittance: N/A; FireRating: INERT
Type - Pset_CoveringFlooring - HasNonSkidSurface: TRUE; HasAntiStaticSurface: FALSE
Type - Pset_Condition - AssessmentDate: N/A; AssessmentCondition: N/A; AssessmentDescription: N/A
Type - Pset_ServiceLife - ServiceLifeDuration: N/A; MeanTimeBetweenFailure: N/A
Type - COBie - AccessibilityPerformance: N/A; AssetIdentifier: N/A; AssetType: FIXED; BarCode: N/A; Category: Pr_35_93_96_19:Ceramic tiles; CodePerformance: BS 5385; Color: GREY; Constituents: N/A; Description: PORCELAIN STONEWARE TILE; DurationUnit: YEAR; ExpectedLife: N/A; Features: N/A; Grade: N/A; InstallationDate: 31/12/1900 23:59:59; Manufacturer: info@refin.it; Material: PORCELAIN STONEWARE; ModelNumber: OQ64; ModelReference: OQ64; Name: Orobica_Grigia_60X60 R; NominalHeight: 9 mm; NominalLength: 600 mm; NominalWidth: 600 mm; ReplacementCost: N/A; SerialNumber: N/A; Shape: SQUARE; Size: 60X60; SustainabilityPerformance: N/A; TagNumber: N/A; WarrantyDescription: N/A; WarrantyDurationLabor: N/A; WarrantyDurationParts: N/A; WarrantyDurationUnit: YEAR; WarrantyGuarantorLabor: N/A; WarrantyGuarantorParts: N/A; WarrantyStartDate: 31/12/1900 23:59:59
Type - DoPAndProductCertification - HarmonizedTechnicalSpecification: EN 14411:2015; DeclarationPerformanceNumber: CPR_01; UniqueIdentificationCodeOfTheProductType: Dry-pressed ceramic tiles,with water absorption Eb<0,5%; SystemOfAssessmentAndVerificationOfCostancyOfPperformance (AVCP): SYSTEM 4; NameAndIdentificationNumberOfNotifiedLaboratory: N/A; CertificateNumber: N/A; ReactionToFire: A1FL/A1; ReleaseOfDangerousSubstanceCadmium: NPD mg/dm2; ReleaseOfDangerousSubstanceLead: NPD mg/dm2; BreakingStrength: > 1300 N; BondStrengthAdhesion: NPD N/mm2; ThermalShockResistance: PASS; Tactility: NPD; DurabilityForInternalUse: PASS; DurabilityExternalUseFreezeThawResistance: PASS; VoluntaryOrNotSubjectToCEMarking: Y/N; IntendedUse: INTERNAL/EXTERNAL; TensileStrengthOrModulusOfRupture: > 35 N/mm2; SlipperinessDIN51130_RampWithOil: R10; SlipperinessDIN51097_RampBarefoot: N/A; SlipperinessDIN51131_Tribometer: N/A; SlipperinessENV12633_PendulumTester: RD = N/A; SlipperinessXPCENTS16165_RampTest: N/A; SlipperinessBCRA_Tribometer: Asciutto > 0,40 / Bagnato > 0,40; SlipperinessBOT3000_Tribometer: > 0,42 Wet; UPECMarkCertification: N/A; UNIMarkCertification: N/A
Type - OtherThecnicalFeatures - DimensionsLengthAndWidth: 0.3; DimensionsThickness: 5; DimensionsStraightness: 0.3; DimensionsRectangularity: 0.3; DimensionsSurfaceFlatness: 0.4; SurfaceQuality: 5; WaterAbsorption: Ev<0.5%; ApparentDensity: N/A g/cm3; ModulusOfRupture: > 35 N/mm2; ImpactResistance: > 0.55; DeepAbrasionResistance: < 175 mm3; SurfaceAbrasionResistance: N/A (classe); LinearThermalExpansion: < 7 10-6/°C; MoistureExpansion: < 0.01; CrazingResistance: N/A; FrostResistance: RESISTENTE; ChemicalResistance: A,LA,HA (classe); StainsResistance: 5 (classe); ThermalConductivity: 1.3 W/m.K; ElectricalConductivity: N/A MW; CompressionResistance: 250 Mpa; HardnessMohsScale: N/A (classe); Light ReflectanceValueLRV: 27 %; LightAndColourFastness: N/A; AntibacterialProperties: N/A (numero puro)
Type - Ambiental Sustainability - EPDType: PRODUCT-SPECIFIC TYPE III EPD; EPDDocument: https://www.refin.it/download/certifications/REFIN_EPD_it.pdf; EnvironmentalProductDeclarationEPD: Y; ISO9001Certification: https://www.refin.it/download/certifications/iso9001.pdf; Ecolabel UE: Y/N; EcolabelCertification: https://www.refin.it/download/certifications/PEF_CeramicheRefin_IT.pdf; EMASCertification/Document: N/A; HealthProductDeclarationHPDCertification/self declaration: N/A; FicheDeDéclarationEnvironnementaleEtSanitaireFDESCertification: https://www.refin.it/download/certifications/refin_fdes.pdf; RecycledContentPreconsumerCertification: https://www.refin.it/download/certifications/leed.pdf; SolarReflectance_InitialValue: 38; SolarReflectance_After3YearValue: N/A; SolarReflectanceCertification: N/A; SolarReflectanceIndexSRICertification: N/A; ZeroVOCMineralBasedProduct: Y; VOCIndoorAirQualityCertification: N/A; RawMaterialSourceAndExtractionDocument: N/A; RecyclableProductPackaging: Y; REACHCompliant: Y; AsbestosFreeMaterial: Y; FormaldehydeFreeMaterial: Y; CAMCompliantDeclaration: N/A; ISO45001Certification: N/A; ISO50001Certification: N/A
Type - Pset_EnvironmentalImpactIndicator - Reference: N/A; FunctionalUnitReference: N/A; Unit: m2; LifeCyclePhase: A1,A2,A3,A4,A5,B1,B2,B3,B4,B5,B6,B7,C1,C2,C3,C4,D; ExpectedServiceLife: 60 YEARS; TotalPrimaryEnergyConsumptionPerUnit: 234; WaterConsumptionPerUnit: 0.0522; HazardousWastePerUnit: 0.00301; NonHazardousWastePerUnit: 10.4; ClimateChangePerUnit: 12.8; AtmosphericAcidificationPerUnit: 0.0485; RenewableEnergyConsumptionPerUnit: 44.5; NonRenewableEnergyConsumptionPerUnit: 189; ResourceDepletionPerUnit: 0.0000365; InertWastePerUnit: N/A; RadioactiveWastePerUnit: 0.00254; StratosphericOzoneLayerDestructionPerUnit: 0.0000000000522; PhotochemicalOzoneFormationPerUnit: 0.00302; EutrophicationPerUnit: 0.00445
Type - Pset_EnvironmentalImpactValues - TotalPrimaryEnergyConsumption: N/A; WaterConsumption: N/A; HazardousWaste: N/A; NonHazardousWaste: N/A; ClimateChange: N/A; AtmosphericAcidification: N/A; RenewableEnergyConsumption: N/A; NonRenewableEnergyConsumption: N/A; ResourceDepletion: N/A; InertWaste: N/A; RadioactiveWaste: N/A; StratosphericOzoneLayerDestruction: N/A; PhotochemicalOzoneFormation: N/A; Eutrophication: N/A; LeadInTime: N/A; Duration: N/A; LeadOutTime: N/A
Pset_ProductRequirements - Category: Floors; sets with these values: 2
Pset_QuantityTakeOff - sets with these values: 2
Pset_SlabCommon - LoadBearing: no; PitchAngle: 0 deg

# IfcSlab: Floor:Floor_Tiles_Refin-Orobica-Grigia-OUT2.0-60x60 OQ66, Floor:Floor_Tiles_Refin-Orobica-Grigia-OUT2.0-60x60 OQ66:350402
In: Level 0
Type - PredefinedType: FLOOR; Material: Orobica-Grigia-OUT2.0-60x60 OQ66 20 mm, <Unnamed> 1 mm
Type - Pset_ConcreteElementGeneral - FireRating: INERT
Type - Pset_ElementShading - Roughness: 914.4 mm; Color: GREY
Type - Pset_FireRatingProperties - SurfaceSpreadOfFlame: INERT
Type - Pset_ManufacturerOccurrence - BarCode: N/A; SerialNumber: N/A
Type - Pset_ManufacturerTypeInformation - ArticleNumber: OQ66; ModelReference: OQ66; ModelLabel: GRIGIA OUT2.0 R 60X60; Manufacturer: info@refin.it; ProductionYear: N/A; GlobalTradeItemNumber: N/A; AssemblyPlace: N/A
Type - Pset_PrecastConcreteElementGeneral - SerialNumber: N/A
Type - Pset_ProductRequirements - Name: Orobica_Grey_OUT2.0_60X60 R; Category: Pr_35_93_96_19:Ceramic tiles
Type - Pset_QuantityTakeOff - Reference: N/A
Type - Pset_ReinforcementBarPitchOfSlab - Description: PORCELAIN STONEWARE TILE; Reference: N/A
Type - Pset_SlabCommon - Reference: N/A; IsExternal: no; AcousticRating: N/A; FireRating: INERT; SurfaceSpreadOfFlame: INERT
Type - Pset_Warranty - WarrantyContent: N/A; Exclusions: N/A; WarrantyEndDate: N/A; IsExtendedWarranty: N/A; WarrantyPeriod: N/A; PointOfContact: N/A
Type - Pset_CoveringCommon - Reference: N/A; Status: N/A; AcousticRating: N/A; FlammabilityRating: INERT; FragilityRating: INERT; Combustible: FALSE; SurfaceSpreadOfFlame: INERT; Finish: MATT; IsExternal: N/A; ThermalTransmittance: N/A; FireRating: INERT
Type - Pset_CoveringFlooring - HasNonSkidSurface: TRUE; HasAntiStaticSurface: FALSE
Type - Pset_Condition - AssessmentDate: N/A; AssessmentCondition: N/A; AssessmentDescription: N/A
Type - Pset_ServiceLife - ServiceLifeDuration: N/A; MeanTimeBetweenFailure: N/A
Type - COBie - AccessibilityPerformance: N/A; AssetIdentifier: N/A; AssetType: FIXED; BarCode: N/A; Category: Pr_35_93_96_19:Ceramic tiles; CodePerformance: BS 5385; Color: GREY; Constituents: N/A; Description: PORCELAIN STONEWARE TILE; DurationUnit: YEAR; ExpectedLife: N/A; Features: N/A; Grade: N/A; InstallationDate: 31/12/1900 23:59:59; Manufacturer: info@refin.it; Material: PORCELAIN STONEWARE; ModelNumber: OQ66; ModelReference: OQ66; Name: Orobica_Grey_OUT2.0_60X60 R; NominalHeight: 20 mm; NominalLength: 600 mm; NominalWidth: 600 mm; ReplacementCost: N/A; SerialNumber: N/A; Shape: SQUARE; Size: 60X60; SustainabilityPerformance: N/A; TagNumber: N/A; WarrantyDescription: N/A; WarrantyDurationLabor: N/A; WarrantyDurationParts: N/A; WarrantyDurationUnit: YEAR; WarrantyGuarantorLabor: N/A; WarrantyGuarantorParts: N/A; WarrantyStartDate: 31/12/1900 23:59:59
Type - DoPAndProductCertification - HarmonizedTechnicalSpecification: EN 14411:2015; DeclarationPerformanceNumber: CPR_01; UniqueIdentificationCodeOfTheProductType: Dry-pressed ceramic tiles,with water absorption Eb<0,5%; SystemOfAssessmentAndVerificationOfCostancyOfPperformance (AVCP): SYSTEM 4; NameAndIdentificationNumberOfNotifiedLaboratory: N/A; CertificateNumber: N/A; ReactionToFire: A1FL/A1; ReleaseOfDangerousSubstanceCadmium: NPD mg/dm2; ReleaseOfDangerousSubstanceLead: NPD mg/dm2; BreakingStrength: > 1300 N; BondStrengthAdhesion: NPD N/mm2; ThermalShockResistance: PASS; Tactility: NPD; DurabilityForInternalUse: PASS; DurabilityExternalUseFreezeThawResistance: PASS; VoluntaryOrNotSubjectToCEMarking: Y/N; IntendedUse: INTERNAL/EXTERNAL; TensileStrengthOrModulusOfRupture: > 35 N/mm2; SlipperinessDIN51130_RampWithOil: R11; SlipperinessDIN51097_RampBarefoot: A+B+C; SlipperinessDIN51131_Tribometer: N/A; SlipperinessENV12633_PendulumTester: RD = N/A; SlipperinessXPCENTS16165_RampTest: N/A; SlipperinessBCRA_Tribometer: Asciutto > 0,40 / Bagnato > 0,40; SlipperinessBOT3000_Tribometer: > 0,42 Wet; UPECMarkCertification: N/A; UNIMarkCertification: N/A
Type - OtherThecnicalFeatures - DimensionsLengthAndWidth: 0.3; DimensionsThickness: 5; DimensionsStraightness: 0.3; DimensionsRectangularity: 0.3; DimensionsSurfaceFlatness: 0.4; SurfaceQuality: 5; WaterAbsorption: Ev<0.5%; ApparentDensity: N/A g/cm3; ModulusOfRupture: > 35 N/mm2; ImpactResistance: > 0.55; DeepAbrasionResistance: < 175 mm3; SurfaceAbrasionResistance: N/A (classe); LinearThermalExpansion: < 7 10-6/°C; MoistureExpansion: < 0.01; CrazingResistance: N/A; FrostResistance: RESISTENTE; ChemicalResistance: A,LA,HA (classe); StainsResistance: 5 (classe); ThermalConductivity: 1.3 W/m.K; ElectricalConductivity: N/A MW; CompressionResistance: 250 Mpa; HardnessMohsScale: N/A (classe); Light ReflectanceValueLRV: 27 %; LightAndColourFastness: N/A; AntibacterialProperties: N/A (numero puro)
Type - Ambiental Sustainability - EPDType: PRODUCT-SPECIFIC TYPE III EPD; EPDDocument: https://www.refin.it/download/certifications/REFIN_EPD_it.pdf; EnvironmentalProductDeclarationEPD: Y; ISO9001Certification: https://www.refin.it/download/certifications/iso9001.pdf; Ecolabel UE: Y/N; EcolabelCertification: https://www.refin.it/download/certifications/PEF_CeramicheRefin_IT.pdf; EMASCertification/Document: N/A; HealthProductDeclarationHPDCertification/self declaration: N/A; FicheDeDéclarationEnvironnementaleEtSanitaireFDESCertification: https://www.refin.it/download/certifications/refin_fdes.pdf; RecycledContentPreconsumerCertification: https://www.refin.it/download/certifications/leed.pdf; SolarReflectance_InitialValue: 38; SolarReflectance_After3YearValue: N/A; SolarReflectanceCertification: N/A; SolarReflectanceIndexSRICertification: N/A; ZeroVOCMineralBasedProduct: Y; VOCIndoorAirQualityCertification: N/A; RawMaterialSourceAndExtractionDocument: N/A; RecyclableProductPackaging: Y; REACHCompliant: Y; AsbestosFreeMaterial: Y; FormaldehydeFreeMaterial: Y; CAMCompliantDeclaration: N/A; ISO45001Certification: N/A; ISO50001Certification: N/A
Type - Pset_EnvironmentalImpactIndicator - Reference: N/A; FunctionalUnitReference: N/A; Unit: m2; LifeCyclePhase: A1,A2,A3,A4,A5,B1,B2,B3,B4,B5,B6,B7,C1,C2,C3,C4,D; ExpectedServiceLife: 60 YEARS; TotalPrimaryEnergyConsumptionPerUnit: 234; WaterConsumptionPerUnit: 0.0522; HazardousWastePerUnit: 0.00301; NonHazardousWastePerUnit: 10.4; ClimateChangePerUnit: 12.8; AtmosphericAcidificationPerUnit: 0.0485; RenewableEnergyConsumptionPerUnit: 44.5; NonRenewableEnergyConsumptionPerUnit: 189; ResourceDepletionPerUnit: 0.0000365; InertWastePerUnit: N/A; RadioactiveWastePerUnit: 0.00254; StratosphericOzoneLayerDestructionPerUnit: 0.0000000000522; PhotochemicalOzoneFormationPerUnit: 0.00302; EutrophicationPerUnit: 0.00445
Type - Pset_EnvironmentalImpactValues - TotalPrimaryEnergyConsumption: N/A; WaterConsumption: N/A; HazardousWaste: N/A; NonHazardousWaste: N/A; ClimateChange: N/A; AtmosphericAcidification: N/A; RenewableEnergyConsumption: N/A; NonRenewableEnergyConsumption: N/A; ResourceDepletion: N/A; InertWaste: N/A; RadioactiveWaste: N/A; StratosphericOzoneLayerDestruction: N/A; PhotochemicalOzoneFormation: N/A; Eutrophication: N/A; LeadInTime: N/A; Duration: N/A; LeadOutTime: N/A
Pset_ProductRequirements - Category: Floors; sets with these values: 2
Pset_QuantityTakeOff - sets with these values: 2
Pset_SlabCommon - LoadBearing: no; PitchAngle: 0 deg

# IfcWallStandardCase: Basic Wall:Wall_Tiles_Refin-Orobica-Antracite-120x120 OQ53, Basic Wall:Wall_Tiles_Refin-Orobica-Antracite-120x120 OQ53:334553
In: Level 0
Type - PredefinedType: STANDARD; Material: <Unnamed> 1 mm, Orobica-Antracite-120x120 OQ53 9 mm
Type - Pset_ConcreteElementGeneral - FireRating: INERT
Type - Pset_ElementShading - Roughness: 914.4 mm; Color: DARK GREY
Type - Pset_FireRatingProperties - SurfaceSpreadOfFlame: INERT
Type - Pset_ManufacturerOccurrence - BarCode: N/A; SerialNumber: N/A
Type - Pset_ManufacturerTypeInformation - ArticleNumber: OQ53; ModelReference: OQ53; ModelLabel: ANTRACITE R 120X120; Manufacturer: info@refin.it; ProductionYear: N/A; GlobalTradeItemNumber: N/A; AssemblyPlace: N/A
Type - Pset_PrecastConcreteElementGeneral - SerialNumber: N/A
Type - Pset_ProductRequirements - Name: Orobica_Antracite_120X120 R; Category: Pr_35_93_96_19:Ceramic tiles
Type - Pset_QuantityTakeOff - Reference: N/A
Type - Pset_ReinforcementBarPitchOfWall - Description: PORCELAIN STONEWARE TILE; Reference: N/A
Type - Pset_WallCommon - Reference: N/A; IsExternal: no; AcousticRating: N/A; FireRating: INERT; SurfaceSpreadOfFlame: INERT
Type - Pset_Warranty - WarrantyContent: N/A; Exclusions: N/A; WarrantyEndDate: N/A; IsExtendedWarranty: N/A; WarrantyPeriod: N/A; PointOfContact: N/A
Type - Pset_CoveringCommon - Reference: N/A; Status: N/A; AcousticRating: N/A; FlammabilityRating: INERT; FragilityRating: INERT; Combustible: FALSE; SurfaceSpreadOfFlame: INERT; Finish: MATT; IsExternal: N/A; ThermalTransmittance: N/A; FireRating: INERT
Type - Pset_CoveringFlooring - HasNonSkidSurface: TRUE; HasAntiStaticSurface: FALSE
Type - Pset_Condition - AssessmentDate: N/A; AssessmentCondition: N/A; AssessmentDescription: N/A
Type - Pset_ServiceLife - ServiceLifeDuration: N/A; MeanTimeBetweenFailure: N/A
Type - COBie - AccessibilityPerformance: N/A; AssetIdentifier: N/A; AssetType: FIXED; BarCode: N/A; Category: Pr_35_93_96_19:Ceramic tiles; CodePerformance: BS 5385; Color: DARK GREY; Constituents: N/A; Description: PORCELAIN STONEWARE TILE; DurationUnit: YEAR; ExpectedLife: N/A; Features: N/A; Grade: N/A; InstallationDate: 31/12/1900 23:59:59; Manufacturer: info@refin.it; Material: PORCELAIN STONEWARE; ModelNumber: OQ53; ModelReference: OQ53; Name: Orobica_Antracite_120X120 R; NominalHeight: 9 mm; NominalLength: 1200 mm; NominalWidth: 1200 mm; ReplacementCost: N/A; SerialNumber: N/A; Shape: SQUARE; Size: 120X120; SustainabilityPerformance: N/A; TagNumber: N/A; WarrantyDescription: N/A; WarrantyDurationLabor: N/A; WarrantyDurationParts: N/A; WarrantyDurationUnit: YEAR; WarrantyGuarantorLabor: N/A; WarrantyGuarantorParts: N/A; WarrantyStartDate: 31/12/1900 23:59:59
Type - DoPAndProductCertification - HarmonizedTechnicalSpecification: EN 14411:2015; DeclarationPerformanceNumber: CPR_01; UniqueIdentificationCodeOfTheProductType: Dry-pressed ceramic tiles,with water absorption Eb<0,5%; SystemOfAssessmentAndVerificationOfCostancyOfPperformance (AVCP): SYSTEM 4; NameAndIdentificationNumberOfNotifiedLaboratory: N/A; CertificateNumber: N/A; ReactionToFire: A1FL/A1; ReleaseOfDangerousSubstanceCadmium: NPD mg/dm2; ReleaseOfDangerousSubstanceLead: NPD mg/dm2; BreakingStrength: > 1300 N; BondStrengthAdhesion: NPD N/mm2; ThermalShockResistance: PASS; Tactility: NPD; DurabilityForInternalUse: PASS; DurabilityExternalUseFreezeThawResistance: PASS; VoluntaryOrNotSubjectToCEMarking: Y/N; IntendedUse: INTERNAL/EXTERNAL; TensileStrengthOrModulusOfRupture: > 35 N/mm2; SlipperinessDIN51130_RampWithOil: R10; SlipperinessDIN51097_RampBarefoot: N/A; SlipperinessDIN51131_Tribometer: N/A; SlipperinessBS7976-2_PendulumTester: N/A; SlipperinessENV12633_PendulumTester: RD = N/A; SlipperinessXPCENTS16165_RampTest: N/A; SlipperinessBCRA_Tribometer: Asciutto > 0,40 / Bagnato > 0,40; SlipperinessBOT3000_Tribometer: > 0,42 Wet; UPECMarkCertification: N/A; UNIMarkCertification: N/A
Type - OtherThecnicalFeatures - DimensionsLengthAndWidth: 0.3; DimensionsThickness: 5; DimensionsStraightness: 0.3; DimensionsRectangularity: 0.3; DimensionsSurfaceFlatness: 0.4; SurfaceQuality: 5; WaterAbsorption: Ev<0.5%; ApparentDensity: N/A g/cm3; ModulusOfRupture: > 35 N/mm2; ImpactResistance: > 0.55; DeepAbrasionResistance: < 175 mm3; SurfaceAbrasionResistance: N/A (classe); LinearThermalExpansion: < 7 10-6/°C; MoistureExpansion: < 0.01; CrazingResistance: N/A; FrostResistance: RESISTENTE; ChemicalResistance: A,LA,HA (classe); StainsResistance: 5 (classe); ThermalConductivity: 1.3 W/m.K; ElectricalConductivity: N/A MW; CompressionResistance: 250 Mpa; HardnessMohsScale: N/A (classe); Light ReflectanceValueLRV: 11 %; LightAndColourFastness: N/A
Type - Ambiental Sustainability - EPDType: PRODUCT-SPECIFIC TYPE III EPD; EPDDocument: https://www.refin.it/download/certifications/REFIN_EPD_it.pdf; EnvironmentalProductDeclarationEPD: Y; ISO9001Certification: https://www.refin.it/download/certifications/iso9001.pdf; Ecolabel UE: Y/N; EcolabelCertification: https://www.refin.it/download/certifications/PEF_CeramicheRefin_IT.pdf; EMASCertification/Document: N/A; HealthProductDeclarationHPDCertification/self declaration: N/A; FicheDeDéclarationEnvironnementaleEtSanitaireFDESCertification: https://www.refin.it/download/certifications/refin_fdes.pdf; RecycledContentPreconsumerCertification: https://www.refin.it/download/certifications/leed.pdf; SolarReflectance_InitialValue: 19; SolarReflectance_After3YearValue: N/A; SolarReflectanceCertification: N/A; SolarReflectanceIndexSRICertification: N/A; ZeroVOCMineralBasedProduct: Y; VOCIndoorAirQualityCertification: N/A; RawMaterialSourceAndExtractionDocument: N/A; RecyclableProductPackaging: Y; REACHCompliant: Y; AsbestosFreeMaterial: Y; FormaldehydeFreeMaterial: Y; CAMCompliantDeclaration: N/A; ISO45001Certification: N/A; ISO50001Certification: N/A
Type - Pset_EnvironmentalImpactIndicator - Reference: N/A; FunctionalUnitReference: N/A; Unit: m2; LifeCyclePhase: A1,A2,A3,A4,A5,B1,B2,B3,B4,B5,B6,B7,C1,C2,C3,C4,D; ExpectedServiceLife: 60 YEARS; TotalPrimaryEnergyConsumptionPerUnit: 234; WaterConsumptionPerUnit: 0.0522; HazardousWastePerUnit: 0.00301; NonHazardousWastePerUnit: 10.4; ClimateChangePerUnit: 12.8; AtmosphericAcidificationPerUnit: 0.0485; RenewableEnergyConsumptionPerUnit: 44.5; NonRenewableEnergyConsumptionPerUnit: 189; ResourceDepletionPerUnit: 0.0000365; InertWastePerUnit: N/A; RadioactiveWastePerUnit: 0.00254; StratosphericOzoneLayerDestructionPerUnit: 0.0000000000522; PhotochemicalOzoneFormationPerUnit: 0.00302; EutrophicationPerUnit: 0.00445
Type - Pset_EnvironmentalImpactValues - TotalPrimaryEnergyConsumption: N/A; WaterConsumption: N/A; HazardousWaste: N/A; NonHazardousWaste: N/A; ClimateChange: N/A; AtmosphericAcidification: N/A; RenewableEnergyConsumption: N/A; NonRenewableEnergyConsumption: N/A; ResourceDepletion: N/A; InertWaste: N/A; RadioactiveWaste: N/A; StratosphericOzoneLayerDestruction: N/A; PhotochemicalOzoneFormation: N/A; Eutrophication: N/A; LeadInTime: N/A; Duration: N/A; LeadOutTime: N/A
Pset_ProductRequirements - Category: Walls; sets with these values: 2
Pset_QuantityTakeOff - sets with these values: 2
Pset_WallCommon - LoadBearing: no; ExtendToStructure: no

# IfcWallStandardCase: Basic Wall:Wall_Tiles_Refin-Orobica-Antracite-60x120 OQ57, Basic Wall:Wall_Tiles_Refin-Orobica-Antracite-60x120 OQ57:333696
In: Level 0
Type - PredefinedType: STANDARD; Material: <Unnamed> 1 mm, Orobica-Antracite-60x120 OQ57 9 mm
Type - Pset_ConcreteElementGeneral - FireRating: INERT
Type - Pset_ElementShading - Roughness: 914.4 mm; Color: DARK GREY
Type - Pset_FireRatingProperties - SurfaceSpreadOfFlame: INERT
Type - Pset_ManufacturerOccurrence - BarCode: N/A; SerialNumber: N/A
Type - Pset_ManufacturerTypeInformation - ArticleNumber: OQ57; ModelReference: OQ57; ModelLabel: ANTRACITE R 60X120; Manufacturer: info@refin.it; ProductionYear: N/A; GlobalTradeItemNumber: N/A; AssemblyPlace: N/A
Type - Pset_PrecastConcreteElementGeneral - SerialNumber: N/A
Type - Pset_ProductRequirements - Name: Orobica_Antracite_60X120 R; Category: Pr_35_93_96_19:Ceramic tiles
Type - Pset_QuantityTakeOff - Reference: N/A
Type - Pset_ReinforcementBarPitchOfWall - Description: PORCELAIN STONEWARE TILE; Reference: N/A
Type - Pset_WallCommon - Reference: N/A; IsExternal: no; AcousticRating: N/A; FireRating: INERT; SurfaceSpreadOfFlame: INERT
Type - Pset_Warranty - WarrantyContent: N/A; Exclusions: N/A; WarrantyEndDate: N/A; IsExtendedWarranty: N/A; WarrantyPeriod: N/A; PointOfContact: N/A
Type - Pset_CoveringCommon - Reference: N/A; Status: N/A; AcousticRating: N/A; FlammabilityRating: INERT; FragilityRating: INERT; Combustible: FALSE; SurfaceSpreadOfFlame: INERT; Finish: MATT; IsExternal: N/A; ThermalTransmittance: N/A; FireRating: INERT
Type - Pset_CoveringFlooring - HasNonSkidSurface: TRUE; HasAntiStaticSurface: FALSE
Type - Pset_Condition - AssessmentDate: N/A; AssessmentCondition: N/A; AssessmentDescription: N/A
Type - Pset_ServiceLife - ServiceLifeDuration: N/A; MeanTimeBetweenFailure: N/A
Type - COBie - AccessibilityPerformance: N/A; AssetIdentifier: N/A; AssetType: FIXED; BarCode: N/A; Category: Pr_35_93_96_19:Ceramic tiles; CodePerformance: BS 5385; Color: DARK GREY; Constituents: N/A; Description: PORCELAIN STONEWARE TILE; DurationUnit: YEAR; ExpectedLife: N/A; Features: N/A; Grade: N/A; InstallationDate: 31/12/1900 23:59:59; Manufacturer: info@refin.it; Material: PORCELAIN STONEWARE; ModelNumber: OQ57; ModelReference: OQ57; Name: Orobica_Antracite_60X120 R; NominalHeight: 9 mm; NominalLength: 600 mm; NominalWidth: 1200 mm; ReplacementCost: N/A; SerialNumber: N/A; Shape: RECTANGULAR; Size: 60X120; SustainabilityPerformance: N/A; TagNumber: N/A; WarrantyDescription: N/A; WarrantyDurationLabor: N/A; WarrantyDurationParts: N/A; WarrantyDurationUnit: YEAR; WarrantyGuarantorLabor: N/A; WarrantyGuarantorParts: N/A; WarrantyStartDate: 31/12/1900 23:59:59
Type - DoPAndProductCertification - HarmonizedTechnicalSpecification: EN 14411:2015; DeclarationPerformanceNumber: CPR_01; UniqueIdentificationCodeOfTheProductType: Dry-pressed ceramic tiles,with water absorption Eb<0,5%; SystemOfAssessmentAndVerificationOfCostancyOfPperformance (AVCP): SYSTEM 4; NameAndIdentificationNumberOfNotifiedLaboratory: N/A; CertificateNumber: N/A; ReactionToFire: A1FL/A1; ReleaseOfDangerousSubstanceCadmium: NPD mg/dm2; ReleaseOfDangerousSubstanceLead: NPD mg/dm2; BreakingStrength: > 1300 N; BondStrengthAdhesion: NPD N/mm2; ThermalShockResistance: PASS; Tactility: NPD; DurabilityForInternalUse: PASS; DurabilityExternalUseFreezeThawResistance: PASS; VoluntaryOrNotSubjectToCEMarking: Y/N; IntendedUse: INTERNAL/EXTERNAL; TensileStrengthOrModulusOfRupture: > 35 N/mm2; SlipperinessDIN51130_RampWithOil: R10; SlipperinessDIN51097_RampBarefoot: N/A; SlipperinessDIN51131_Tribometer: N/A; SlipperinessBS7976-2_PendulumTester: N/A; SlipperinessENV12633_PendulumTester: RD = N/A; SlipperinessXPCENTS16165_RampTest: N/A; SlipperinessBCRA_Tribometer: Asciutto > 0,40 / Bagnato > 0,40; SlipperinessBOT3000_Tribometer: > 0,42 Wet; UPECMarkCertification: N/A; UNIMarkCertification: N/A
Type - OtherThecnicalFeatures - DimensionsLengthAndWidth: 0.3; DimensionsThickness: 5; DimensionsStraightness: 0.3; DimensionsRectangularity: 0.3; DimensionsSurfaceFlatness: 0.4; SurfaceQuality: 5; WaterAbsorption: Ev<0.5%; ApparentDensity: N/A g/cm3; ModulusOfRupture: > 35 N/mm2; ImpactResistance: > 0.55; DeepAbrasionResistance: < 175 mm3; SurfaceAbrasionResistance: N/A (classe); LinearThermalExpansion: < 7 10-6/°C; MoistureExpansion: < 0.01; CrazingResistance: N/A; FrostResistance: RESISTENTE; ChemicalResistance: A,LA,HA (classe); StainsResistance: 5 (classe); ThermalConductivity: 1.3 W/m.K; ElectricalConductivity: N/A MW; CompressionResistance: 250 Mpa; HardnessMohsScale: N/A (classe); Light ReflectanceValueLRV: 11 %; LightAndColourFastness: N/A
Type - Ambiental Sustainability - EPDType: PRODUCT-SPECIFIC TYPE III EPD; EPDDocument: https://www.refin.it/download/certifications/REFIN_EPD_it.pdf; EnvironmentalProductDeclarationEPD: Y; ISO9001Certification: https://www.refin.it/download/certifications/iso9001.pdf; Ecolabel UE: Y/N; EcolabelCertification: https://www.refin.it/download/certifications/PEF_CeramicheRefin_IT.pdf; EMASCertification/Document: N/A; HealthProductDeclarationHPDCertification/self declaration: N/A; FicheDeDéclarationEnvironnementaleEtSanitaireFDESCertification: https://www.refin.it/download/certifications/refin_fdes.pdf; RecycledContentPreconsumerCertification: https://www.refin.it/download/certifications/leed.pdf; SolarReflectance_InitialValue: 19; SolarReflectance_After3YearValue: N/A; SolarReflectanceCertification: N/A; SolarReflectanceIndexSRICertification: N/A; ZeroVOCMineralBasedProduct: Y; VOCIndoorAirQualityCertification: N/A; RawMaterialSourceAndExtractionDocument: N/A; RecyclableProductPackaging: Y; REACHCompliant: Y; AsbestosFreeMaterial: Y; FormaldehydeFreeMaterial: Y; CAMCompliantDeclaration: N/A; ISO45001Certification: N/A; ISO50001Certification: N/A
Type - Pset_EnvironmentalImpactIndicator - Reference: N/A; FunctionalUnitReference: N/A; Unit: m2; LifeCyclePhase: A1,A2,A3,A4,A5,B1,B2,B3,B4,B5,B6,B7,C1,C2,C3,C4,D; ExpectedServiceLife: 60 YEARS; TotalPrimaryEnergyConsumptionPerUnit: 234; WaterConsumptionPerUnit: 0.0522; HazardousWastePerUnit: 0.00301; NonHazardousWastePerUnit: 10.4; ClimateChangePerUnit: 12.8; AtmosphericAcidificationPerUnit: 0.0485; RenewableEnergyConsumptionPerUnit: 44.5; NonRenewableEnergyConsumptionPerUnit: 189; ResourceDepletionPerUnit: 0.0000365; InertWastePerUnit: N/A; RadioactiveWastePerUnit: 0.00254; StratosphericOzoneLayerDestructionPerUnit: 0.0000000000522; PhotochemicalOzoneFormationPerUnit: 0.00302; EutrophicationPerUnit: 0.00445
Type - Pset_EnvironmentalImpactValues - TotalPrimaryEnergyConsumption: N/A; WaterConsumption: N/A; HazardousWaste: N/A; NonHazardousWaste: N/A; ClimateChange: N/A; AtmosphericAcidification: N/A; RenewableEnergyConsumption: N/A; NonRenewableEnergyConsumption: N/A; ResourceDepletion: N/A; InertWaste: N/A; RadioactiveWaste: N/A; StratosphericOzoneLayerDestruction: N/A; PhotochemicalOzoneFormation: N/A; Eutrophication: N/A; LeadInTime: N/A; Duration: N/A; LeadOutTime: N/A
Pset_ProductRequirements - Category: Walls; sets with these values: 2
Pset_QuantityTakeOff - sets with these values: 2
Pset_WallCommon - LoadBearing: no; ExtendToStructure: no

# IfcWallStandardCase: Basic Wall:Wall_Tiles_Refin-Orobica-Antracite-60x60 OQ61, Basic Wall:Wall_Tiles_Refin-Orobica-Antracite-60x60 OQ61:334895
In: Level 0
Type - PredefinedType: STANDARD; Material: <Unnamed> 1 mm, Orobica-Antracite-60x60 OQ61 9 mm
Type - Pset_ConcreteElementGeneral - FireRating: INERT
Type - Pset_ElementShading - Roughness: 914.4 mm; Color: DARK GREY
Type - Pset_FireRatingProperties - SurfaceSpreadOfFlame: INERT
Type - Pset_ManufacturerOccurrence - BarCode: N/A; SerialNumber: N/A
Type - Pset_ManufacturerTypeInformation - ArticleNumber: OQ61; ModelReference: OQ61; ModelLabel: ANTRACITE R 60X60; Manufacturer: info@refin.it; ProductionYear: N/A; GlobalTradeItemNumber: N/A; AssemblyPlace: N/A
Type - Pset_PrecastConcreteElementGeneral - SerialNumber: N/A
Type - Pset_ProductRequirements - Name: Orobica_Antracite_60X60 R; Category: Pr_35_93_96_19:Ceramic tiles
Type - Pset_QuantityTakeOff - Reference: N/A
Type - Pset_ReinforcementBarPitchOfWall - Description: PORCELAIN STONEWARE TILE; Reference: N/A
Type - Pset_WallCommon - Reference: N/A; IsExternal: no; AcousticRating: N/A; FireRating: INERT; SurfaceSpreadOfFlame: INERT
Type - Pset_Warranty - WarrantyContent: N/A; Exclusions: N/A; WarrantyEndDate: N/A; IsExtendedWarranty: N/A; WarrantyPeriod: N/A; PointOfContact: N/A
Type - Pset_CoveringCommon - Reference: N/A; Status: N/A; AcousticRating: N/A; FlammabilityRating: INERT; FragilityRating: INERT; Combustible: FALSE; SurfaceSpreadOfFlame: INERT; Finish: MATT; IsExternal: N/A; ThermalTransmittance: N/A; FireRating: INERT
Type - Pset_CoveringFlooring - HasNonSkidSurface: TRUE; HasAntiStaticSurface: FALSE
Type - Pset_Condition - AssessmentDate: N/A; AssessmentCondition: N/A; AssessmentDescription: N/A
Type - Pset_ServiceLife - ServiceLifeDuration: N/A; MeanTimeBetweenFailure: N/A
Type - COBie - AccessibilityPerformance: N/A; AssetIdentifier: N/A; AssetType: FIXED; BarCode: N/A; Category: Pr_35_93_96_19:Ceramic tiles; CodePerformance: BS 5385; Color: DARK GREY; Constituents: N/A; Description: PORCELAIN STONEWARE TILE; DurationUnit: YEAR; ExpectedLife: N/A; Features: N/A; Grade: N/A; InstallationDate: 31/12/1900 23:59:59; Manufacturer: info@refin.it; Material: PORCELAIN STONEWARE; ModelNumber: OQ61; ModelReference: OQ61; Name: Orobica_Antracite_60X60 R; NominalHeight: 9 mm; NominalLength: 600 mm; NominalWidth: 600 mm; ReplacementCost: N/A; SerialNumber: N/A; Shape: SQUARE; Size: 60X60; SustainabilityPerformance: N/A; TagNumber: N/A; WarrantyDescription: N/A; WarrantyDurationLabor: N/A; WarrantyDurationParts: N/A; WarrantyDurationUnit: YEAR; WarrantyGuarantorLabor: N/A; WarrantyGuarantorParts: N/A; WarrantyStartDate: 31/12/1900 23:59:59
Type - DoPAndProductCertification - HarmonizedTechnicalSpecification: EN 14411:2015; DeclarationPerformanceNumber: CPR_01; UniqueIdentificationCodeOfTheProductType: Dry-pressed ceramic tiles,with water absorption Eb<0,5%; SystemOfAssessmentAndVerificationOfCostancyOfPperformance (AVCP): SYSTEM 4; NameAndIdentificationNumberOfNotifiedLaboratory: N/A; CertificateNumber: N/A; ReactionToFire: A1FL/A1; ReleaseOfDangerousSubstanceCadmium: NPD mg/dm2; ReleaseOfDangerousSubstanceLead: NPD mg/dm2; BreakingStrength: > 1300 N; BondStrengthAdhesion: NPD N/mm2; ThermalShockResistance: PASS; Tactility: NPD; DurabilityForInternalUse: PASS; DurabilityExternalUseFreezeThawResistance: PASS; VoluntaryOrNotSubjectToCEMarking: Y/N; IntendedUse: INTERNAL/EXTERNAL; TensileStrengthOrModulusOfRupture: > 35 N/mm2; SlipperinessDIN51130_RampWithOil: R10; SlipperinessDIN51097_RampBarefoot: N/A; SlipperinessDIN51131_Tribometer: N/A; SlipperinessBS7976-2_PendulumTester: N/A; SlipperinessENV12633_PendulumTester: RD = N/A; SlipperinessXPCENTS16165_RampTest: N/A; SlipperinessBCRA_Tribometer: Asciutto > 0,40 / Bagnato > 0,40; SlipperinessBOT3000_Tribometer: > 0,42 Wet; UPECMarkCertification: N/A; UNIMarkCertification: N/A
